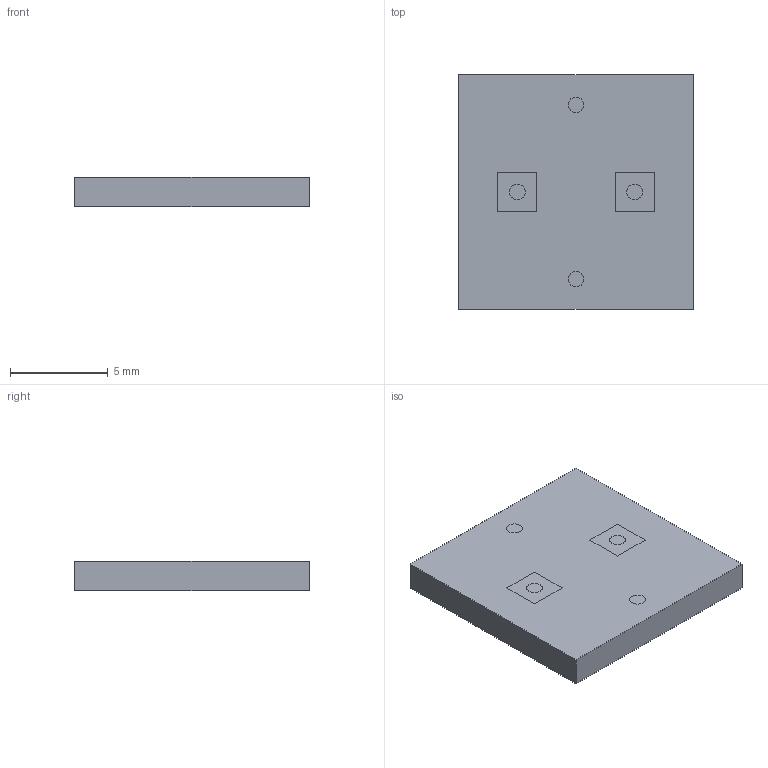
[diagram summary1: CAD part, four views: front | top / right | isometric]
STEP (ISO 10303-21) file: header records copied from the file, then geometry measured from it (millimetres).
FILE_DESCRIPTION(('Open CASCADE Model'),'2;1');
FILE_NAME('Open CASCADE Shape Model','2026-11-27T13:54:34',('Author'),( 'Open CASCADE'),'Open CASCADE STEP processor 7.9','Open CASCADE 7.9' ,'Unknown');
FILE_SCHEMA(('AUTOMOTIVE_DESIGN { 1 0 10303 214 1 1 1 1 }'));
Length unit declared in the file: millimetre
Products named in the file (3): manifold_N26; fluid; solid
Assembly tree (2 placements, depth 2):
  manifold_N26
    fluid
    solid
Bounding box: 12 x 12 x 1.5 mm (x, y, z)
Volume: 216 mm3; surface area: 1127.2 mm2
Topology: 2 solids, 2 shells, 698 faces, 2168 edges, 1338 vertices
Faces by surface type: plane 690, cylinder 8
Full cylindrical faces by diameter (mm): 0.8 x8
Entity records: 51994 total; most frequent: CARTESIAN_POINT 9451, DIRECTION 7714, LINE 6052, VECTOR 6052, ORIENTED_EDGE 4336, PCURVE 4336, DEFINITIONAL_REPRESENTATION 4336, EDGE_CURVE 2168
One B-rep face of a CAD part: STEP entity #27883.
In plain terms, the planar face has unit normal (-1, 0, 0).
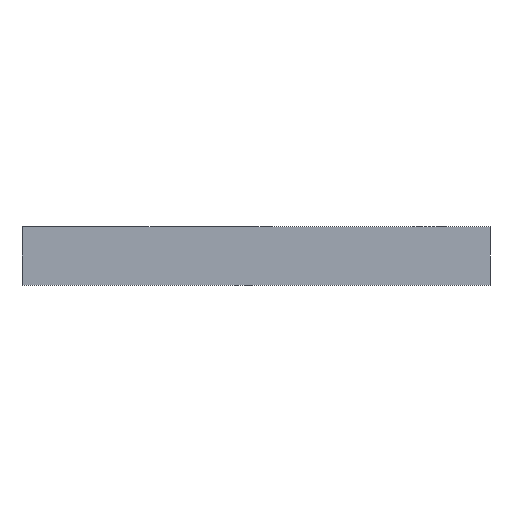
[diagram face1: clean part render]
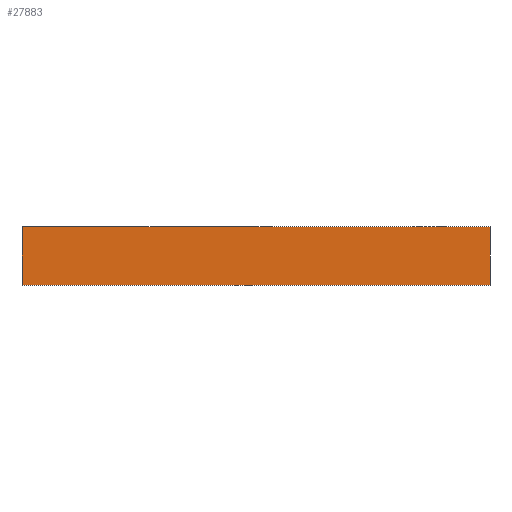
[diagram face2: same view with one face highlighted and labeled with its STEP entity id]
Its self-contained STEP definition (entity closure, numbers rounded to 3 decimals):
#27883 = ADVANCED_FACE('',(#27884),#27898,.F.);
#27884 = FACE_BOUND('',#27885,.F.);
#27885 = EDGE_LOOP('',(#27886,#27921,#27949,#27977));
#27886 = ORIENTED_EDGE('',*,*,#27887,.F.);
#27887 = EDGE_CURVE('',#27888,#27890,#27892,.T.);
#27888 = VERTEX_POINT('',#27889);
#27889 = CARTESIAN_POINT('',(0.,0.,0.));
#27890 = VERTEX_POINT('',#27891);
#27891 = CARTESIAN_POINT('',(0.,0.,1.5));
#27892 = SURFACE_CURVE('',#27893,(#27897,#27909),.PCURVE_S1.);
#27893 = LINE('',#27894,#27895);
#27894 = CARTESIAN_POINT('',(0.,0.,0.));
#27895 = VECTOR('',#27896,1.);
#27896 = DIRECTION('',(0.,0.,1.));
#27897 = PCURVE('',#27898,#27903);
#27898 = PLANE('',#27899);
#27899 = AXIS2_PLACEMENT_3D('',#27900,#27901,#27902);
#27900 = CARTESIAN_POINT('',(0.,0.,0.));
#27901 = DIRECTION('',(1.,0.,-0.));
#27902 = DIRECTION('',(0.,0.,1.));
#27903 = DEFINITIONAL_REPRESENTATION('',(#27904),#27908);
#27904 = LINE('',#27905,#27906);
#27905 = CARTESIAN_POINT('',(0.,0.));
#27906 = VECTOR('',#27907,1.);
#27907 = DIRECTION('',(1.,0.));
#27908 = ( GEOMETRIC_REPRESENTATION_CONTEXT(2) 
PARAMETRIC_REPRESENTATION_CONTEXT() REPRESENTATION_CONTEXT('2D SPACE',''
  ) );
#27909 = PCURVE('',#27910,#27915);
#27910 = PLANE('',#27911);
#27911 = AXIS2_PLACEMENT_3D('',#27912,#27913,#27914);
#27912 = CARTESIAN_POINT('',(0.,0.,0.));
#27913 = DIRECTION('',(-0.,1.,0.));
#27914 = DIRECTION('',(0.,0.,1.));
#27915 = DEFINITIONAL_REPRESENTATION('',(#27916),#27920);
#27916 = LINE('',#27917,#27918);
#27917 = CARTESIAN_POINT('',(0.,0.));
#27918 = VECTOR('',#27919,1.);
#27919 = DIRECTION('',(1.,0.));
#27920 = ( GEOMETRIC_REPRESENTATION_CONTEXT(2) 
PARAMETRIC_REPRESENTATION_CONTEXT() REPRESENTATION_CONTEXT('2D SPACE',''
  ) );
#27921 = ORIENTED_EDGE('',*,*,#27922,.T.);
#27922 = EDGE_CURVE('',#27888,#27923,#27925,.T.);
#27923 = VERTEX_POINT('',#27924);
#27924 = CARTESIAN_POINT('',(0.,12.,0.));
#27925 = SURFACE_CURVE('',#27926,(#27930,#27937),.PCURVE_S1.);
#27926 = LINE('',#27927,#27928);
#27927 = CARTESIAN_POINT('',(0.,0.,0.));
#27928 = VECTOR('',#27929,1.);
#27929 = DIRECTION('',(-0.,1.,0.));
#27930 = PCURVE('',#27898,#27931);
#27931 = DEFINITIONAL_REPRESENTATION('',(#27932),#27936);
#27932 = LINE('',#27933,#27934);
#27933 = CARTESIAN_POINT('',(0.,0.));
#27934 = VECTOR('',#27935,1.);
#27935 = DIRECTION('',(0.,-1.));
#27936 = ( GEOMETRIC_REPRESENTATION_CONTEXT(2) 
PARAMETRIC_REPRESENTATION_CONTEXT() REPRESENTATION_CONTEXT('2D SPACE',''
  ) );
#27937 = PCURVE('',#27938,#27943);
#27938 = PLANE('',#27939);
#27939 = AXIS2_PLACEMENT_3D('',#27940,#27941,#27942);
#27940 = CARTESIAN_POINT('',(0.,0.,0.));
#27941 = DIRECTION('',(0.,0.,1.));
#27942 = DIRECTION('',(1.,0.,-0.));
#27943 = DEFINITIONAL_REPRESENTATION('',(#27944),#27948);
#27944 = LINE('',#27945,#27946);
#27945 = CARTESIAN_POINT('',(0.,0.));
#27946 = VECTOR('',#27947,1.);
#27947 = DIRECTION('',(0.,1.));
#27948 = ( GEOMETRIC_REPRESENTATION_CONTEXT(2) 
PARAMETRIC_REPRESENTATION_CONTEXT() REPRESENTATION_CONTEXT('2D SPACE',''
  ) );
#27949 = ORIENTED_EDGE('',*,*,#27950,.T.);
#27950 = EDGE_CURVE('',#27923,#27951,#27953,.T.);
#27951 = VERTEX_POINT('',#27952);
#27952 = CARTESIAN_POINT('',(0.,12.,1.5));
#27953 = SURFACE_CURVE('',#27954,(#27958,#27965),.PCURVE_S1.);
#27954 = LINE('',#27955,#27956);
#27955 = CARTESIAN_POINT('',(0.,12.,0.));
#27956 = VECTOR('',#27957,1.);
#27957 = DIRECTION('',(0.,0.,1.));
#27958 = PCURVE('',#27898,#27959);
#27959 = DEFINITIONAL_REPRESENTATION('',(#27960),#27964);
#27960 = LINE('',#27961,#27962);
#27961 = CARTESIAN_POINT('',(0.,-12.));
#27962 = VECTOR('',#27963,1.);
#27963 = DIRECTION('',(1.,0.));
#27964 = ( GEOMETRIC_REPRESENTATION_CONTEXT(2) 
PARAMETRIC_REPRESENTATION_CONTEXT() REPRESENTATION_CONTEXT('2D SPACE',''
  ) );
#27965 = PCURVE('',#27966,#27971);
#27966 = PLANE('',#27967);
#27967 = AXIS2_PLACEMENT_3D('',#27968,#27969,#27970);
#27968 = CARTESIAN_POINT('',(0.,12.,0.));
#27969 = DIRECTION('',(-0.,1.,0.));
#27970 = DIRECTION('',(0.,0.,1.));
#27971 = DEFINITIONAL_REPRESENTATION('',(#27972),#27976);
#27972 = LINE('',#27973,#27974);
#27973 = CARTESIAN_POINT('',(0.,0.));
#27974 = VECTOR('',#27975,1.);
#27975 = DIRECTION('',(1.,0.));
#27976 = ( GEOMETRIC_REPRESENTATION_CONTEXT(2) 
PARAMETRIC_REPRESENTATION_CONTEXT() REPRESENTATION_CONTEXT('2D SPACE',''
  ) );
#27977 = ORIENTED_EDGE('',*,*,#27978,.F.);
#27978 = EDGE_CURVE('',#27890,#27951,#27979,.T.);
#27979 = SURFACE_CURVE('',#27980,(#27984,#27991),.PCURVE_S1.);
#27980 = LINE('',#27981,#27982);
#27981 = CARTESIAN_POINT('',(0.,0.,1.5));
#27982 = VECTOR('',#27983,1.);
#27983 = DIRECTION('',(-0.,1.,0.));
#27984 = PCURVE('',#27898,#27985);
#27985 = DEFINITIONAL_REPRESENTATION('',(#27986),#27990);
#27986 = LINE('',#27987,#27988);
#27987 = CARTESIAN_POINT('',(1.5,0.));
#27988 = VECTOR('',#27989,1.);
#27989 = DIRECTION('',(0.,-1.));
#27990 = ( GEOMETRIC_REPRESENTATION_CONTEXT(2) 
PARAMETRIC_REPRESENTATION_CONTEXT() REPRESENTATION_CONTEXT('2D SPACE',''
  ) );
#27991 = PCURVE('',#27992,#27997);
#27992 = PLANE('',#27993);
#27993 = AXIS2_PLACEMENT_3D('',#27994,#27995,#27996);
#27994 = CARTESIAN_POINT('',(0.,0.,1.5));
#27995 = DIRECTION('',(0.,0.,1.));
#27996 = DIRECTION('',(1.,0.,-0.));
#27997 = DEFINITIONAL_REPRESENTATION('',(#27998),#28002);
#27998 = LINE('',#27999,#28000);
#27999 = CARTESIAN_POINT('',(0.,0.));
#28000 = VECTOR('',#28001,1.);
#28001 = DIRECTION('',(0.,1.));
#28002 = ( GEOMETRIC_REPRESENTATION_CONTEXT(2) 
PARAMETRIC_REPRESENTATION_CONTEXT() REPRESENTATION_CONTEXT('2D SPACE',''
  ) );
